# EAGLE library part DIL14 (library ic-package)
Dual In Line / Socket

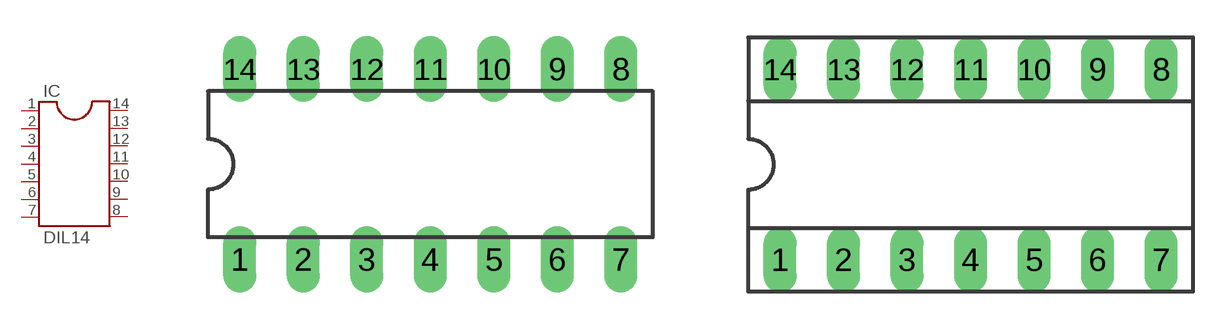
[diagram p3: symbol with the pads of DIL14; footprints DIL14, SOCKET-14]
Designator prefix IC

## DIL14  [DIL14]
1  1  pas
2  2  pas
3  3  pas
4  4  pas
5  5  pas
6  6  pas
7  7  pas
8  8  pas
9  9  pas
10  10  pas
11  11  pas
12  12  pas
13  13  pas
14  14  pas

## DIL14S  [SOCKET-14]
Pads as for DIL14

## Footprint DIL14 (pad centres in mm)
Dual In Line Package
drill 0.813 long: 1 -7.62,-3.81; 2 -5.08,-3.81; 3 -2.54,-3.81; 4 0,-3.81; 5 2.54,-3.81; 6 5.08,-3.81; 7 7.62,-3.81; 8 7.62,3.81; 9 5.08,3.81; 10 2.54,3.81; 11 0,3.81; 12 -2.54,3.81; 13 -5.08,3.81; 14 -7.62,3.81

## Footprint SOCKET-14 (pad centres in mm)
Dual In Line Socket
drill 0.813 long: 1 -7.62,-3.81; 2 -5.08,-3.81; 3 -2.54,-3.81; 4 0,-3.81; 5 2.54,-3.81; 6 5.08,-3.81; 7 7.62,-3.81; 8 7.62,3.81; 9 5.08,3.81; 10 2.54,3.81; 11 0,3.81; 12 -2.54,3.81; 13 -5.08,3.81; 14 -7.62,3.81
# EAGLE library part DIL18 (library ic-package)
Dual In Line / Socket

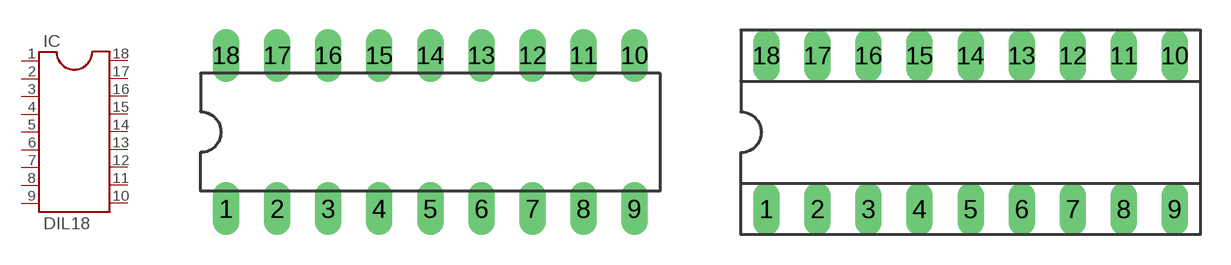
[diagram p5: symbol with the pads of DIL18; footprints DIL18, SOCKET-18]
Designator prefix IC

## DIL18  [DIL18]
1  1  pas
2  2  pas
3  3  pas
4  4  pas
5  5  pas
6  6  pas
7  7  pas
8  8  pas
9  9  pas
10  10  pas
11  11  pas
12  12  pas
13  13  pas
14  14  pas
15  15  pas
16  16  pas
17  17  pas
18  18  pas

## DIL18S  [SOCKET-18]
Pads as for DIL18

## Footprint DIL18 (pad centres in mm)
Dual In Line Package
drill 0.813 long: 1 -10.16,-3.81; 2 -7.62,-3.81; 3 -5.08,-3.81; 4 -2.54,-3.81; 5 0,-3.81; 6 2.54,-3.81; 7 5.08,-3.81; 8 7.62,-3.81; 9 10.16,-3.81; 10 10.16,3.81; 11 7.62,3.81; 12 5.08,3.81; 13 2.54,3.81; 14 0,3.81; 15 -2.54,3.81; 16 -5.08,3.81; 17 -7.62,3.81; 18 -10.16,3.81

## Footprint SOCKET-18 (pad centres in mm)
Dual In Line Socket
drill 0.813 long: 1 -10.16,-3.81; 2 -7.62,-3.81; 3 -5.08,-3.81; 4 -2.54,-3.81; 5 0,-3.81; 6 2.54,-3.81; 7 5.08,-3.81; 8 7.62,-3.81; 9 10.16,-3.81; 10 10.16,3.81; 11 7.62,3.81; 12 5.08,3.81; 13 2.54,3.81; 14 0,3.81; 15 -2.54,3.81; 16 -5.08,3.81; 17 -7.62,3.81; 18 -10.16,3.81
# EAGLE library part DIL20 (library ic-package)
Dual In Line / Socket

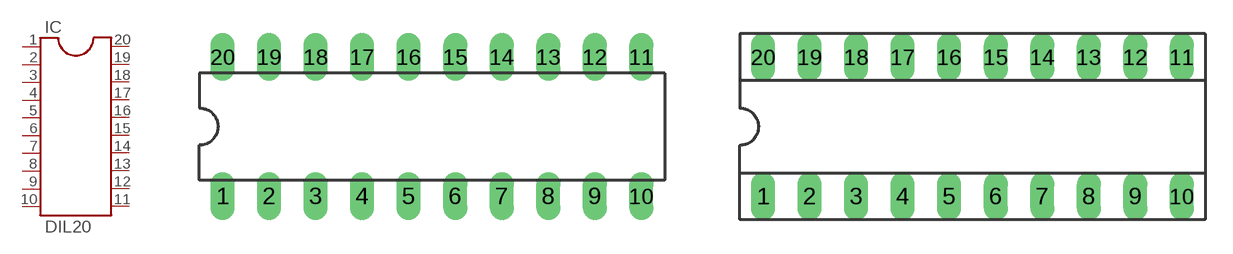
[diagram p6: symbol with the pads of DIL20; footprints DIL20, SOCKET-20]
Designator prefix IC

## DIL20  [DIL20]
1  1  pas
2  2  pas
3  3  pas
4  4  pas
5  5  pas
6  6  pas
7  7  pas
8  8  pas
9  9  pas
10  10  pas
11  11  pas
12  12  pas
13  13  pas
14  14  pas
15  15  pas
16  16  pas
17  17  pas
18  18  pas
19  19  pas
20  20  pas

## DIL20S  [SOCKET-20]
Pads as for DIL20

## Footprint DIL20 (pad centres in mm)
Dual In Line Package
drill 0.813 long: 1 -11.43,-3.81; 2 -8.89,-3.81; 3 -6.35,-3.81; 4 -3.81,-3.81; 5 -1.27,-3.81; 6 1.27,-3.81; 7 3.81,-3.81; 8 6.35,-3.81; 9 8.89,-3.81; 10 11.43,-3.81; 11 11.43,3.81; 12 8.89,3.81; 13 6.35,3.81; 14 3.81,3.81; 15 1.27,3.81; 16 -1.27,3.81; 17 -3.81,3.81; 18 -6.35,3.81; 19 -8.89,3.81; 20 -11.43,3.81

## Footprint SOCKET-20 (pad centres in mm)
Dual In Line Socket
drill 0.813 long: 1 -11.43,-3.81; 2 -8.89,-3.81; 3 -6.35,-3.81; 4 -3.81,-3.81; 5 -1.27,-3.81; 6 1.27,-3.81; 7 3.81,-3.81; 8 6.35,-3.81; 9 8.89,-3.81; 10 11.43,-3.81; 11 11.43,3.81; 12 8.89,3.81; 13 6.35,3.81; 14 3.81,3.81; 15 1.27,3.81; 16 -1.27,3.81; 17 -3.81,3.81; 18 -6.35,3.81; 19 -8.89,3.81; 20 -11.43,3.81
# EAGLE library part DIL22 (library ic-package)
Dual In Line / Socket

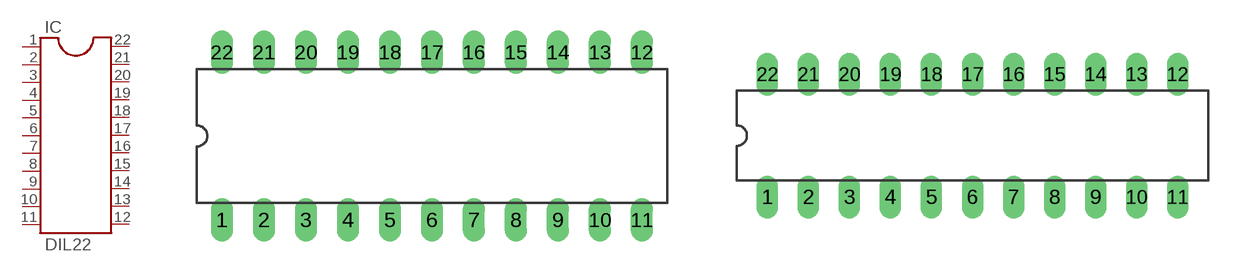
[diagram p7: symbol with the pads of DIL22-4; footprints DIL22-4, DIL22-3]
Designator prefix IC

## DIL22-4  [DIL22-4]
1  1  pas
2  2  pas
3  3  pas
4  4  pas
5  5  pas
6  6  pas
7  7  pas
8  8  pas
9  9  pas
10  10  pas
11  11  pas
12  12  pas
13  13  pas
14  14  pas
15  15  pas
16  16  pas
17  17  pas
18  18  pas
19  19  pas
20  20  pas
21  21  pas
22  22  pas

## DIL22-3  [DIL22-3]
Pads as for DIL22-4

## DIL22S-3  [SOCKET-22S]
Pads as for DIL22-4

## Footprint DIL22-4 (pad centres in mm)
Dual In Line 0.4 inch
drill 0.813 long: 1 -12.7,-5.08; 2 -10.16,-5.08; 3 -7.62,-5.08; 4 -5.08,-5.08; 5 -2.54,-5.08; 6 0,-5.08; 7 2.54,-5.08; 8 5.08,-5.08; 9 7.62,-5.08; 10 10.16,-5.08; 11 12.7,-5.08; 12 12.7,5.08; 13 10.16,5.08; 14 7.62,5.08; 15 5.08,5.08; 16 2.54,5.08; 17 0,5.08; 18 -2.54,5.08; 19 -5.08,5.08; 20 -7.62,5.08; 21 -10.16,5.08; 22 -12.7,5.08

## Footprint DIL22-3 (pad centres in mm)
Dual In Line Package 0.3 inch
drill 0.813 long: 1 -12.7,-3.81; 2 -10.16,-3.81; 3 -7.62,-3.81; 4 -5.08,-3.81; 5 -2.54,-3.81; 6 0,-3.81; 7 2.54,-3.81; 8 5.08,-3.81; 9 7.62,-3.81; 10 10.16,-3.81; 11 12.7,-3.81; 12 12.7,3.81; 13 10.16,3.81; 14 7.62,3.81; 15 5.08,3.81; 16 2.54,3.81; 17 0,3.81; 18 -2.54,3.81; 19 -5.08,3.81; 20 -7.62,3.81; 21 -10.16,3.81; 22 -12.7,3.81

## Footprint SOCKET-22S (pad centres in mm)
Dual In Line Socket Small
drill 0.813 long: 1 -12.7,-3.81; 2 -10.16,-3.81; 3 -7.62,-3.81; 4 -5.08,-3.81; 5 -2.54,-3.81; 6 0,-3.81; 7 2.54,-3.81; 8 5.08,-3.81; 9 7.62,-3.81; 10 10.16,-3.81; 11 12.7,-3.81; 12 12.7,3.81; 13 10.16,3.81; 14 7.62,3.81; 15 5.08,3.81; 16 2.54,3.81; 17 0,3.81; 18 -2.54,3.81; 19 -5.08,3.81; 20 -7.62,3.81; 21 -10.16,3.81; 22 -12.7,3.81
